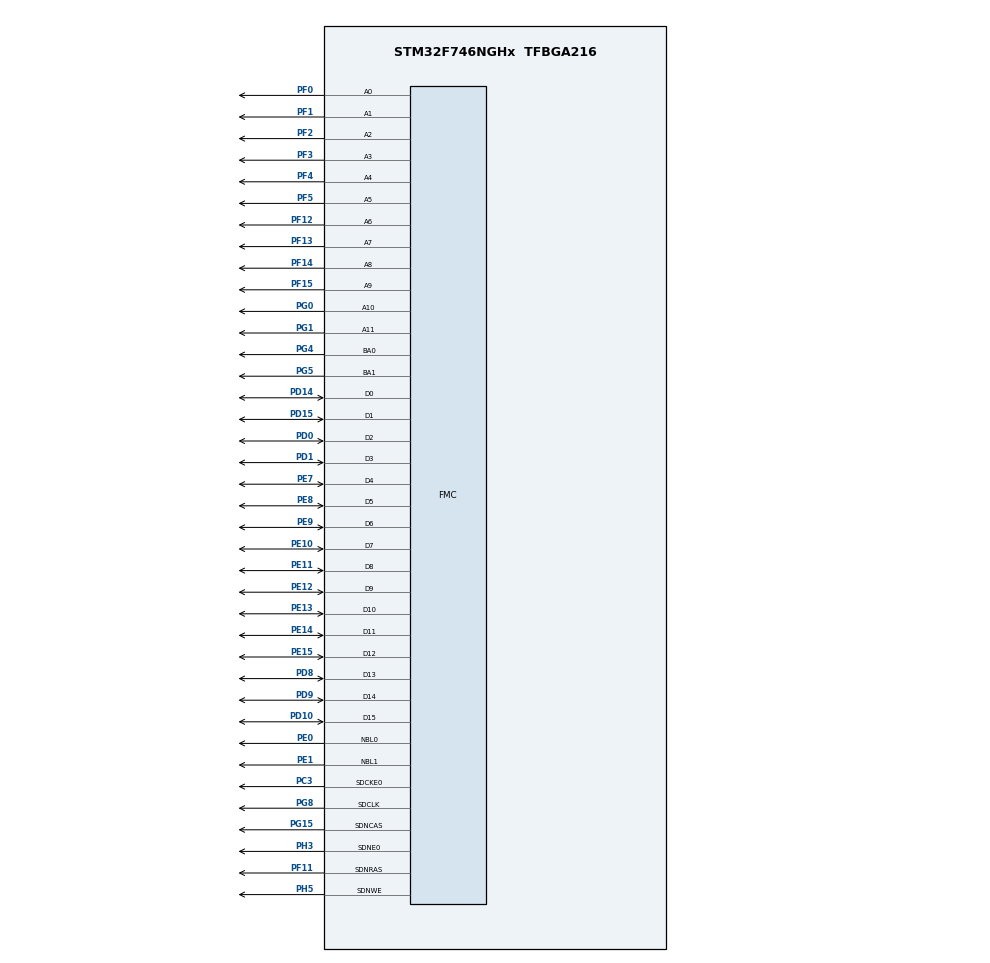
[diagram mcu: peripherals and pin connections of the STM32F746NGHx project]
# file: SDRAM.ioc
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CORTEX_M7.ART_ACCLERATOR_ENABLE=0
CORTEX_M7.CPU_DCache=Disabled
CORTEX_M7.CPU_ICache=Disabled
CORTEX_M7.PREFETCH_ENABLE=0
FMC.CASLatency1=FMC_SDRAM_CAS_LATENCY_2
FMC.ExitSelfRefreshDelay1=7
FMC.LoadToActiveDelay1=2
FMC.RCDDelay1=2
FMC.RPDelay1=2
FMC.ReadBurst1=FMC_SDRAM_RBURST_ENABLE
FMC.RowCycleDelay1=7
FMC.SDClockPeriod1=FMC_SDRAM_CLOCK_PERIOD_2
FMC.SDClockPeriod2=FMC_SDRAM_CLOCK_PERIOD_2
FMC.SelfRefreshTime1=4
FMC.WriteRecoveryTime1=3
Mcu.Family=STM32F7
Mcu.Name=STM32F746NGHx
Mcu.Package=TFBGA216
NVIC.PriorityGroup=NVIC_PRIORITYGROUP_4
PC3.Mode=SdramChipSelect1_1
PC3.Signal=FMC_SDCKE0
PD0.Signal=FMC_D2_DA2
PD1.Signal=FMC_D3_DA3
PD10.Signal=FMC_D15_DA15
PD14.Signal=FMC_D0_DA0
PD15.Signal=FMC_D1_DA1
PD8.Signal=FMC_D13_DA13
PD9.Signal=FMC_D14_DA14
PE0.Signal=FMC_NBL0
PE1.Signal=FMC_NBL1
PE10.Signal=FMC_D7_DA7
PE11.Signal=FMC_D8_DA8
PE12.Signal=FMC_D9_DA9
PE13.Signal=FMC_D10_DA10
PE14.Signal=FMC_D11_DA11
PE15.Signal=FMC_D12_DA12
PE7.Signal=FMC_D4_DA4
PE8.Signal=FMC_D5_DA5
PE9.Signal=FMC_D6_DA6
PF0.Signal=FMC_A0
PF1.Signal=FMC_A1
PF11.Signal=FMC_SDNRAS
PF12.Signal=FMC_A6
PF13.Signal=FMC_A7
PF14.Signal=FMC_A8
PF15.Signal=FMC_A9
PF2.Signal=FMC_A2
PF3.Signal=FMC_A3
PF4.Signal=FMC_A4
PF5.Signal=FMC_A5
PG0.Signal=FMC_A10
PG1.Signal=FMC_A11
PG15.Signal=FMC_SDNCAS
PG4.Signal=FMC_A14_BA0
PG5.Signal=FMC_A15_BA1
PG8.Signal=FMC_SDCLK
PH0/OSC_IN.Mode=HSE-External-Clock-Source
PH0/OSC_IN.Signal=RCC_OSC_IN
PH1/OSC_OUT.Mode=HSE-External-Clock-Source
PH1/OSC_OUT.Signal=RCC_OSC_OUT
PH3.Mode=SdramChipSelect1_1
PH3.Signal=FMC_SDNE0
PH5.Signal=FMC_SDNWE
ProjectManager.HeapSize=0x2000
ProjectManager.StackSize=0x2000
ProjectManager.TargetToolchain=MDK-ARM V5
RCC.AHBFreq_Value=200000000
RCC.APB1CLKDivider=RCC_HCLK_DIV4
RCC.APB1Freq_Value=50000000
RCC.APB1TimFreq_Value=100000000
RCC.APB2CLKDivider=RCC_HCLK_DIV2
RCC.APB2Freq_Value=100000000
RCC.APB2TimFreq_Value=200000000
RCC.CortexFreq_Value=200000000
RCC.HCLKFreq_Value=200000000
RCC.HSE_VALUE=25000000
RCC.HSI_VALUE=16000000
RCC.LSE_VALUE=32768
RCC.PLLM=12
RCC.PLLQ=7
RCC.PLLSourceVirtual=RCC_PLLSOURCE_HSE
RCC.SYSCLKFreq_VALUE=200000000
RCC.SYSCLKSource=RCC_SYSCLKSOURCE_PLLCLK
RCC.USBFreq_Value=57142857.14285714
RCC.VCOOutputFreq_Value=400000000
SH.FMC_A0.0=FMC_A0,12b-sda1
SH.FMC_A1.0=FMC_A1,12b-sda1
SH.FMC_A10.0=FMC_A10,12b-sda1
SH.FMC_A11.0=FMC_A11,12b-sda1
SH.FMC_A14_BA0.0=FMC_BA0,FourSdramBanks1
SH.FMC_A15_BA1.0=FMC_BA1,FourSdramBanks1
SH.FMC_A2.0=FMC_A2,12b-sda1
SH.FMC_A3.0=FMC_A3,12b-sda1
SH.FMC_A4.0=FMC_A4,12b-sda1
SH.FMC_A5.0=FMC_A5,12b-sda1
SH.FMC_A6.0=FMC_A6,12b-sda1
SH.FMC_A7.0=FMC_A7,12b-sda1
SH.FMC_A8.0=FMC_A8,12b-sda1
SH.FMC_A9.0=FMC_A9,12b-sda1
SH.FMC_D0_DA0.0=FMC_D0,sd-16b-d1
SH.FMC_D10_DA10.0=FMC_D10,sd-16b-d1
SH.FMC_D11_DA11.0=FMC_D11,sd-16b-d1
SH.FMC_D12_DA12.0=FMC_D12,sd-16b-d1
SH.FMC_D13_DA13.0=FMC_D13,sd-16b-d1
SH.FMC_D14_DA14.0=FMC_D14,sd-16b-d1
SH.FMC_D15_DA15.0=FMC_D15,sd-16b-d1
SH.FMC_D1_DA1.0=FMC_D1,sd-16b-d1
SH.FMC_D2_DA2.0=FMC_D2,sd-16b-d1
SH.FMC_D3_DA3.0=FMC_D3,sd-16b-d1
SH.FMC_D4_DA4.0=FMC_D4,sd-16b-d1
SH.FMC_D5_DA5.0=FMC_D5,sd-16b-d1
SH.FMC_D6_DA6.0=FMC_D6,sd-16b-d1
SH.FMC_D7_DA7.0=FMC_D7,sd-16b-d1
SH.FMC_D8_DA8.0=FMC_D8,sd-16b-d1
SH.FMC_D9_DA9.0=FMC_D9,sd-16b-d1
SH.FMC_NBL0.0=FMC_NBL0,Sd2ByteEnable1
SH.FMC_NBL1.0=FMC_NBL1,Sd2ByteEnable1
SH.FMC_SDCLK.0=FMC_SDCLK,12b-sda1
SH.FMC_SDNCAS.0=FMC_SDNCAS,12b-sda1
SH.FMC_SDNRAS.0=FMC_SDNRAS,12b-sda1
SH.FMC_SDNWE.0=FMC_SDNWE,12b-sda1
board=SDRAM

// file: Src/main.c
/**
  ******************************************************************************
  * File Name          : main.c
  * Description        : Main program body
  ******************************************************************************
  ** This notice applies to any and all portions of this file
  * that are not between comment pairs USER CODE BEGIN and
  * USER CODE END. Other portions of this file, whether
  * inserted by the user or by software development tools
  * are owned by their respective copyright owners.
  *
  * COPYRIGHT(c) 2017 STMicroelectronics
  *
  * Redistribution and use in source and binary forms, with or without modification,
  * are permitted provided that the following conditions are met:
  *   1. Redistributions of source code must retain the above copyright notice,
  *      this list of conditions and the following disclaimer.
  *   2. Redistributions in binary form must reproduce the above copyright notice,
  *      this list of conditions and the following disclaimer in the documentation
  *      and/or other materials provided with the distribution.
  *   3. Neither the name of STMicroelectronics nor the names of its contributors
  *      may be used to endorse or promote products derived from this software
  *      without specific prior written permission.
  *
  * THIS SOFTWARE IS PROVIDED BY THE COPYRIGHT HOLDERS AND CONTRIBUTORS "AS IS"
  * AND ANY EXPRESS OR IMPLIED WARRANTIES, INCLUDING, BUT NOT LIMITED TO, THE
  * IMPLIED WARRANTIES OF MERCHANTABILITY AND FITNESS FOR A PARTICULAR PURPOSE ARE
  * DISCLAIMED. IN NO EVENT SHALL THE COPYRIGHT HOLDER OR CONTRIBUTORS BE LIABLE
  * FOR ANY DIRECT, INDIRECT, INCIDENTAL, SPECIAL, EXEMPLARY, OR CONSEQUENTIAL
  * DAMAGES (INCLUDING, BUT NOT LIMITED TO, PROCUREMENT OF SUBSTITUTE GOODS OR
  * SERVICES; LOSS OF USE, DATA, OR PROFITS; OR BUSINESS INTERRUPTION) HOWEVER
  * CAUSED AND ON ANY THEORY OF LIABILITY, WHETHER IN CONTRACT, STRICT LIABILITY,
  * OR TORT (INCLUDING NEGLIGENCE OR OTHERWISE) ARISING IN ANY WAY OUT OF THE USE
  * OF THIS SOFTWARE, EVEN IF ADVISED OF THE POSSIBILITY OF SUCH DAMAGE.
  *
  ******************************************************************************
  */

#include "main.h"
#include "stm32f7xx_hal.h"

SDRAM_HandleTypeDef hsdram1;

/* USER CODE BEGIN PV */
/* Private variables ---------------------------------------------------------*/

/* USER CODE END PV */

void SystemClock_Config(void);
static void MX_GPIO_Init(void);
static void MX_FMC_Init(void);

/* USER CODE BEGIN PFP */
/* Private function prototypes -----------------------------------------------*/

/* USER CODE END PFP */

int main(void)
{

  /* MCU Configuration----------------------------------------------------------*/

  /* Reset of all peripherals, Initializes the Flash interface and the Systick. */
  HAL_Init();

  /* Configure the system clock */
  SystemClock_Config();

  /* Initialize all configured peripherals */
  MX_GPIO_Init();
  MX_FMC_Init();

  /* Infinite loop */
  /* USER CODE BEGIN WHILE */

  while (1)
  {

		uint32_t *pAddress = (uint32_t*)(0xC0000000);
		uint16_t tmp1[100];
		uint16_t tmp2[100];
		uint32_t i;

		for(i=0;i<100;i++)
		{
			tmp2[i] = i;
		}

		HAL_SDRAM_Write_16b(  &hsdram1, pAddress, tmp2, 100 );
		HAL_SDRAM_Read_16b( &hsdram1, pAddress, tmp1, 100 );

  /* USER CODE END WHILE */

  }

}

/** System Clock Configuration
*/
void SystemClock_Config(void)
{

  RCC_OscInitTypeDef RCC_OscInitStruct;
  RCC_ClkInitTypeDef RCC_ClkInitStruct;

    /**Configure the main internal regulator output voltage
    */
  __HAL_RCC_PWR_CLK_ENABLE();

  __HAL_PWR_VOLTAGESCALING_CONFIG(PWR_REGULATOR_VOLTAGE_SCALE2);

    /**Initializes the CPU, AHB and APB busses clocks
    */
  RCC_OscInitStruct.OscillatorType = RCC_OSCILLATORTYPE_HSE;
  RCC_OscInitStruct.HSEState = RCC_HSE_BYPASS;
  RCC_OscInitStruct.PLL.PLLState = RCC_PLL_ON;
  RCC_OscInitStruct.PLL.PLLSource = RCC_PLLSOURCE_HSE;
  RCC_OscInitStruct.PLL.PLLM = 25;
  RCC_OscInitStruct.PLL.PLLN = 336;
  RCC_OscInitStruct.PLL.PLLP = RCC_PLLP_DIV2;
  RCC_OscInitStruct.PLL.PLLQ = 7;
  if (HAL_RCC_OscConfig(&RCC_OscInitStruct) != HAL_OK)
  {
    _Error_Handler(__FILE__, __LINE__);
  }

    /**Initializes the CPU, AHB and APB busses clocks
    */
  RCC_ClkInitStruct.ClockType = RCC_CLOCKTYPE_HCLK|RCC_CLOCKTYPE_SYSCLK
                              |RCC_CLOCKTYPE_PCLK1|RCC_CLOCKTYPE_PCLK2;
  RCC_ClkInitStruct.SYSCLKSource = RCC_SYSCLKSOURCE_PLLCLK;
  RCC_ClkInitStruct.AHBCLKDivider = RCC_SYSCLK_DIV1;
  RCC_ClkInitStruct.APB1CLKDivider = RCC_HCLK_DIV4;
  RCC_ClkInitStruct.APB2CLKDivider = RCC_HCLK_DIV2;

  if (HAL_RCC_ClockConfig(&RCC_ClkInitStruct, FLASH_LATENCY_5) != HAL_OK)
  {
    _Error_Handler(__FILE__, __LINE__);
  }

    /**Configure the Systick interrupt time
    */
  HAL_SYSTICK_Config(HAL_RCC_GetHCLKFreq()/1000);

    /**Configure the Systick
    */
  HAL_SYSTICK_CLKSourceConfig(SYSTICK_CLKSOURCE_HCLK);

  /* SysTick_IRQn interrupt configuration */
  HAL_NVIC_SetPriority(SysTick_IRQn, 0, 0);
}

#define REFRESH_COUNT                    ((uint32_t)0x0603)   /* SDRAM refresh counter (100Mhz SD clock) */
#define SDRAM_TIMEOUT                    ((uint32_t)0xFFFF)

#define SDRAM_MODEREG_BURST_LENGTH_1             ((uint16_t)0x0000)
#define SDRAM_MODEREG_BURST_LENGTH_2             ((uint16_t)0x0001)
#define SDRAM_MODEREG_BURST_LENGTH_4             ((uint16_t)0x0002)
#define SDRAM_MODEREG_BURST_LENGTH_8             ((uint16_t)0x0004)
#define SDRAM_MODEREG_BURST_TYPE_SEQUENTIAL      ((uint16_t)0x0000)
#define SDRAM_MODEREG_BURST_TYPE_INTERLEAVED     ((uint16_t)0x0008)
#define SDRAM_MODEREG_CAS_LATENCY_2              ((uint16_t)0x0020)
#define SDRAM_MODEREG_CAS_LATENCY_3              ((uint16_t)0x0030)
#define SDRAM_MODEREG_OPERATING_MODE_STANDARD    ((uint16_t)0x0000)
#define SDRAM_MODEREG_WRITEBURST_MODE_PROGRAMMED ((uint16_t)0x0000)
#define SDRAM_MODEREG_WRITEBURST_MODE_SINGLE     ((uint16_t)0x0200)

/* SDRAM Initialization Sequence */
static void SDRAM_Initialization_Sequence(uint32_t RefreshCount)
{
  __IO uint32_t tmpmrd = 0;

	FMC_SDRAM_CommandTypeDef Command;

  /* Step 1: Configure a clock configuration enable command */
  Command.CommandMode            = FMC_SDRAM_CMD_CLK_ENABLE;
  Command.CommandTarget          = FMC_SDRAM_CMD_TARGET_BANK1;
  Command.AutoRefreshNumber      = 1;
  Command.ModeRegisterDefinition = 0;

  /* Send the command */
  HAL_SDRAM_SendCommand(&hsdram1, &Command, SDRAM_TIMEOUT);

  /* Step 2: Insert 100 us minimum delay */
  /* Inserted delay is equal to 1 ms due to systick time base unit (ms) */
  HAL_Delay(1);

  /* Step 3: Configure a PALL (precharge all) command */
  Command.CommandMode            = FMC_SDRAM_CMD_PALL;
  Command.CommandTarget          = FMC_SDRAM_CMD_TARGET_BANK1;
  Command.AutoRefreshNumber      = 1;
  Command.ModeRegisterDefinition = 0;

  /* Send the command */
  HAL_SDRAM_SendCommand(&hsdram1, &Command, SDRAM_TIMEOUT);

  /* Step 4: Configure an Auto Refresh command */
  Command.CommandMode            = FMC_SDRAM_CMD_AUTOREFRESH_MODE;
  Command.CommandTarget          = FMC_SDRAM_CMD_TARGET_BANK1;
  Command.AutoRefreshNumber      = 8;
  Command.ModeRegisterDefinition = 0;

  /* Send the command */
  HAL_SDRAM_SendCommand(&hsdram1, &Command, SDRAM_TIMEOUT);

  /* Step 5: Program the external memory mode register */
  tmpmrd = (uint32_t)SDRAM_MODEREG_BURST_LENGTH_1          |\
                     SDRAM_MODEREG_BURST_TYPE_SEQUENTIAL   |\
                     SDRAM_MODEREG_CAS_LATENCY_2           |\
                     SDRAM_MODEREG_OPERATING_MODE_STANDARD |\
                     SDRAM_MODEREG_WRITEBURST_MODE_SINGLE;

  Command.CommandMode            = FMC_SDRAM_CMD_LOAD_MODE;
  Command.CommandTarget          = FMC_SDRAM_CMD_TARGET_BANK1;
  Command.AutoRefreshNumber      = 1;
  Command.ModeRegisterDefinition = tmpmrd;

  /* Send the command */
  HAL_SDRAM_SendCommand(&hsdram1, &Command, SDRAM_TIMEOUT);

  /* Step 6: Set the refresh rate counter */
  /* Set the device refresh rate */
  HAL_SDRAM_ProgramRefreshRate(&hsdram1, RefreshCount);
}

/* FMC initialization function */
static void MX_FMC_Init(void)
{
  FMC_SDRAM_TimingTypeDef SdramTiming;

  /** Perform the SDRAM1 memory initialization sequence
  */
  hsdram1.Instance = FMC_SDRAM_DEVICE;
  /* hsdram1.Init */
  hsdram1.Init.SDBank = FMC_SDRAM_BANK1;
  hsdram1.Init.ColumnBitsNumber = FMC_SDRAM_COLUMN_BITS_NUM_8;
  hsdram1.Init.RowBitsNumber = FMC_SDRAM_ROW_BITS_NUM_12;
  hsdram1.Init.MemoryDataWidth = FMC_SDRAM_MEM_BUS_WIDTH_16;
  hsdram1.Init.InternalBankNumber = FMC_SDRAM_INTERN_BANKS_NUM_4;
  hsdram1.Init.CASLatency = FMC_SDRAM_CAS_LATENCY_2;
  hsdram1.Init.WriteProtection = FMC_SDRAM_WRITE_PROTECTION_DISABLE;
  hsdram1.Init.SDClockPeriod = FMC_SDRAM_CLOCK_PERIOD_2;
  hsdram1.Init.ReadBurst = FMC_SDRAM_RBURST_ENABLE;
  hsdram1.Init.ReadPipeDelay = FMC_SDRAM_RPIPE_DELAY_0;
  /* SdramTiming */
  SdramTiming.LoadToActiveDelay = 2;
  SdramTiming.ExitSelfRefreshDelay = 7;
  SdramTiming.SelfRefreshTime = 4;
  SdramTiming.RowCycleDelay = 7;
  SdramTiming.WriteRecoveryTime = 3;
  SdramTiming.RPDelay = 2;
  SdramTiming.RCDDelay = 2;

	HAL_SDRAM_MspInit( &hsdram1 );

  if (HAL_SDRAM_Init(&hsdram1, &SdramTiming) != HAL_OK)
  {
    _Error_Handler(__FILE__, __LINE__);
  }

  /* SDRAM initialization sequence */
  SDRAM_Initialization_Sequence(REFRESH_COUNT);

}

/** Configure pins as
        * Analog
        * Input
        * Output
        * EVENT_OUT
        * EXTI
*/
static void MX_GPIO_Init(void)
{

  /* GPIO Ports Clock Enable */
  __HAL_RCC_GPIOH_CLK_ENABLE();
  __HAL_RCC_GPIOG_CLK_ENABLE();
  __HAL_RCC_GPIOF_CLK_ENABLE();
  __HAL_RCC_GPIOE_CLK_ENABLE();
  __HAL_RCC_GPIOD_CLK_ENABLE();
  __HAL_RCC_GPIOC_CLK_ENABLE();
  __HAL_RCC_GPIOB_CLK_ENABLE();
  __HAL_RCC_GPIOA_CLK_ENABLE();

}

void _Error_Handler(char * file, int line)
{
  while(1)
  {
  }
}

/************************ (C) COPYRIGHT STMicroelectronics *****END OF FILE****/
